VERSION 5.7 ;
  NOWIREEXTENSIONATPIN ON ;
  DIVIDERCHAR "/" ;
  BUSBITCHARS "[]" ;
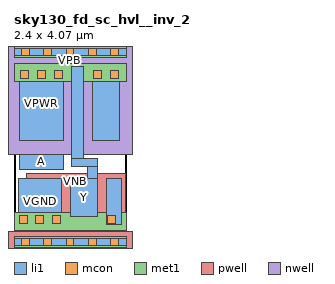
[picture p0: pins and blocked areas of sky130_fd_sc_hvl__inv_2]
MACRO sky130_fd_sc_hvl__inv_2
  CLASS BLOCK ;
  FOREIGN sky130_fd_sc_hvl__inv_2 ;
  ORIGIN 0.000 0.000 ;
  SIZE 2.400 BY 4.070 ;
  PIN A
    ANTENNAGATEAREA 2.250000 ;
    PORT
      LAYER li1 ;
        RECT 0.125 1.550 1.070 1.880 ;
    END
  END A
  PIN VGND
    USE GROUND ;
    PORT
      LAYER li1 ;
        RECT 0.090 0.365 1.020 1.370 ;
        RECT 1.980 0.365 2.310 1.370 ;
      LAYER mcon ;
        RECT 0.110 0.395 0.280 0.565 ;
        RECT 0.470 0.395 0.640 0.565 ;
        RECT 0.830 0.395 1.000 0.565 ;
        RECT 2.010 0.395 2.180 0.565 ;
      LAYER met1 ;
        RECT 0.000 0.255 2.400 0.625 ;
    END
  END VGND
  PIN VNB
    ANTENNADIFFAREA 0.408000 ;
    PORT
      LAYER pwell ;
        RECT 0.270 0.215 2.380 1.460 ;
        RECT -0.130 -0.215 2.530 0.215 ;
      LAYER li1 ;
        RECT 0.000 -0.085 2.400 0.085 ;
      LAYER mcon ;
        RECT 0.155 -0.085 0.325 0.085 ;
        RECT 0.635 -0.085 0.805 0.085 ;
        RECT 1.115 -0.085 1.285 0.085 ;
        RECT 1.595 -0.085 1.765 0.085 ;
        RECT 2.075 -0.085 2.245 0.085 ;
      LAYER met1 ;
        RECT 0.000 -0.115 2.400 0.115 ;
    END
  END VNB
  PIN VPB
    ANTENNADIFFAREA 0.408000 ;
    PORT
      LAYER nwell ;
        RECT -0.330 1.885 2.730 4.485 ;
      LAYER li1 ;
        RECT 0.000 3.985 2.400 4.155 ;
      LAYER mcon ;
        RECT 0.155 3.985 0.325 4.155 ;
        RECT 0.635 3.985 0.805 4.155 ;
        RECT 1.115 3.985 1.285 4.155 ;
        RECT 1.595 3.985 1.765 4.155 ;
        RECT 2.075 3.985 2.245 4.155 ;
      LAYER met1 ;
        RECT 0.000 3.955 2.400 4.185 ;
    END
  END VPB
  PIN VPWR
    USE POWER ;
    PORT
      LAYER li1 ;
        RECT 0.110 2.175 1.060 3.755 ;
        RECT 1.680 2.175 2.270 3.755 ;
      LAYER mcon ;
        RECT 0.140 3.505 0.310 3.675 ;
        RECT 0.500 3.505 0.670 3.675 ;
        RECT 0.860 3.505 1.030 3.675 ;
        RECT 1.710 3.505 1.880 3.675 ;
        RECT 2.070 3.505 2.240 3.675 ;
      LAYER met1 ;
        RECT 0.000 3.445 2.400 3.815 ;
    END
  END VPWR
  PIN Y
    ANTENNADIFFAREA 0.630000 ;
    PORT
      LAYER li1 ;
        RECT 1.240 1.780 1.490 3.755 ;
        RECT 1.240 1.610 1.795 1.780 ;
        RECT 1.565 1.370 1.795 1.610 ;
        RECT 1.200 0.540 1.795 1.370 ;
    END
  END Y
END sky130_fd_sc_hvl__inv_2
END LIBRARY

